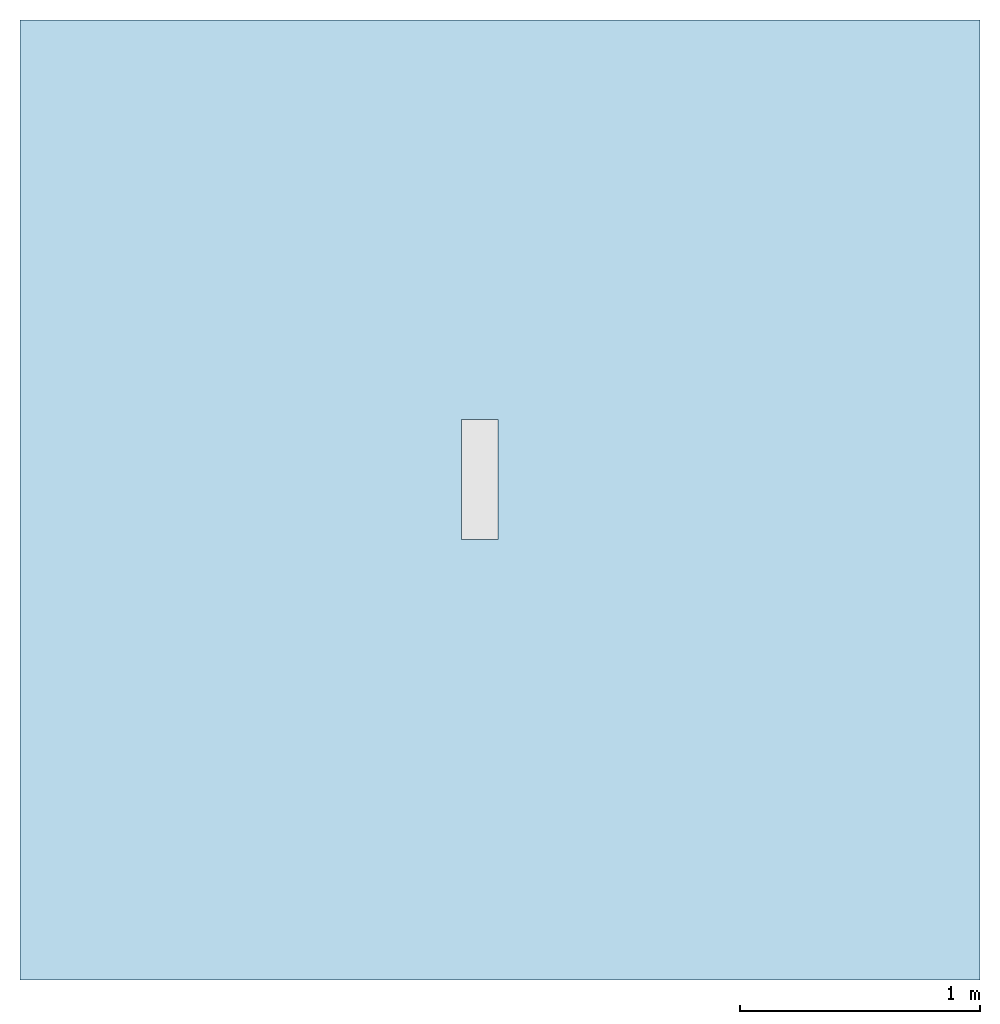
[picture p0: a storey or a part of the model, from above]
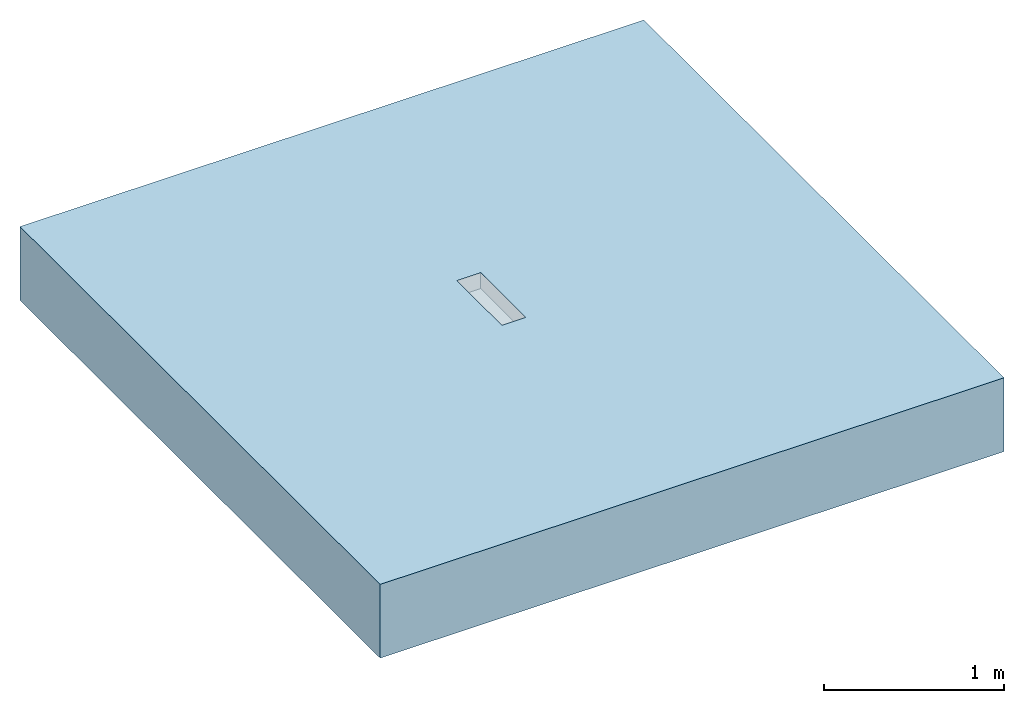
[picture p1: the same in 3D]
Properties of the parts of a building model (IFC2X3)

# File
Description: ViewDefinition [CoordinationView]
File name: 105178 - End Outlet Channel - 500mm LG - Invert Depth 95mm.ifc
Time: 2014-03-19T14:24:23
Written by: Autodesk Revit 2013
Made in: 20120221_2030(x64)

# IfcProject, Project Number
LongName: Project Name; Phase: Project Status

# IfcSite, Default
RefLatitude: 42, 21, 30, 344238; RefLongitude: -71, -3, -35, -194702; RefElevation: 0 mm

# IfcBuilding
Pset_BuildingCommon - NumberOfStoreys: 1
Other - Client Name: Owner; Project Name: Project Name; Project Number: Project Number; Project Address: ## Street City, State Zip; Project Issue Date: Issue Date; Project Status: Project Status

# IfcBuildingStorey, Level 1
LongName: Level 1; Elevation: 0 mm
Constraints - Elevation Base: 0; Elevation: 0 mm
Graphics - Line Weight: 1; Line Pattern: Center; Symbol at End 1 Default: no; Symbol at End 2 Default: yes; Color: 0; Symbol: M_Level Head - Circle: M_Level Head - Circle
Dimensions - Computation Height: 0 mm
Identity Data - Name: Level 1; Building Story: yes; Structural: no

# IfcFlowTerminal: 105178 - End Outlet Channel - 500mm LG - Invert Depth 95mm, ACO BD Modular 125 Inline Outlet Units:105178 - End Outlet Channel - 500mm LG - Invert Depth 95mm:105178 - End Outlet Channel - 500mm LG - Invert Depth 95mm:227583
In: Level 1
Material: Stainless Steel AISI 304, Polystyrene, High Impact
Identity Data - Watermarked With: BIM Manager Premium Suite.; Fax: +44 (0)1462 851490; Telephone: +44 (0)1462 816666; Watermark1: This file is the property of ACO Technologies PLC.; Website: www.acobd.com; E-mail Technical: abdtechnical@aco.co.uk; E-mail Sales: abdcommercial@aco.co.uk; Watermarked By: www.acobd.com; Address: ACO Business Centre, Caxton Road, Bedford, MK41 0LF; Manufacturer: ACO Building Drainage; Watermark2: This file is water marked and users are prohibited to reproduce, adapt, distribute this information.; Cost: 0; Mark: 5
Construction - 105519 - Slotted Locked - Stainless Steel 304 - 500mm long: no; 105537 - Intercept Locked - Stainless Steel 304 - 500mm long: no; 105529 - Quadrato - Stainless Steel 304 - 1000mm long: no; 105518 - Slotted Locked - Stainless Steel 304 - 1000mm long: no; 96818 - Grating - Heal Safe - Stainless Steel 304 - 1000mm long: no; 105845 - Slip Resistant Intercept - Stainless Steel 304 - 1000mm long: no; 105520 - Slotted Locked - Stainless Steel 304 - 1000mm long: no; 96819 - Grating - Heal Safe - Stainless Steel 304 - 500mm long: no; 105846 - Slip Resistant Intercept - Stainless Steel 304 - 500mm long: no; 21720 - Grating - Plain Mesh - Stainless Steel 304 - 500mm long: no; 105539 - Intercept - Stainless Steel 304 - 500mm long: no; 402072 - Grating - Heal Safe Locked - Stainless Steel 304 - 500mm long: no; 105536 - Intercept Locked - Stainless Steel 304 - 1000mm long: no; 105528 - Quadrato Locked - Stainless Steel 304 - 500mm long: no; 21810 - Grating - Slip Resistant Mesh - Stainless Steel 304 - 1000mm long: no; 21510 - Sediment Basket: no; 26270_PVC Infill: yes; 105521 - Slotted Locked - Stainless Steel 304 - 500mm long: no; 97235 - Sieve: no; 21820 - Grating - Plain Mesh - Stainless Steel 304 - 1000mm long: no; 21710 - Grating - Slip Resistant Mesh - Stainless Steel 304 - 500mm long: no; 21741 - Ladder - Stainless Steel 304 - 1000mm long: no; End Plate Invert 2: no; 21690 - Plastic - White Plastic - 1000mm long: no; 105505 - Perforated Locked - Stainless Steel 304 - 500mm long: no; 105538 - Intercept - Stainless Steel 304 - 1000mm long: no; 21610 - Grating - Slip Resistant Mesh - Stainless Steel 304 - 1000mm long: no; 105527 - Quadrato Locked - Stainless Steel 304 - 1000mm long: no; 21910 - Grating - Slip Resistant Mesh - Stainless Steel 304 - 500mm long: no; 21790 - Plastic - White Plastic - 500mm long: no; 105848 - Slip Resistant Intercept Locked - Stainless Steel 304 - 500mm long: no; 105847 - Slip Resistant Intercept Locked - Stainless Steel 304 - 1000mm long: no; 21740 - Ladder - Stainless Steel 304 - 500mm long: no; End Plate Invert 1: no; 49061 & 49062_Vinyl Seal: no; 21920 - Grating - Plain Mesh - Stainless Steel 304 - 500mm long: no; 402071 - Grating - Heal Safe Locked - Stainless Steel 304 - 1000mm long: no; 105530 - Quadrato - Stainless Steel 304 - 500mm long: no; 105841 - Slip Resistant Quadrato - Stainless Steel 304 - 1000mm long: no; 97217 - Outlet Foul Air Trap: no; 21620 - Grating - Plain Mesh - Stainless Steel 304 - 1000mm long: no; 105504 - Perforated Locked - Stainless Steel 304 - 1000mm long: no; 10735 - Composite - White Composite - 500mm long: no; 105843 - Slip Resistant Quadrato Locked - Stainless Steel 304 - 1000mm long: no; 105842 - Slip Resistant Quadrato - Stainless Steel 304 - 500mm long: no; 15704 - Composite - Black Composite - 500mm long: no; 105844 - Slip Resistant Quadrato Locked - Stainless Steel 304 - 500mm long: no; Detail 50mm: no; Detail 110mm: no; Detail 125mm: no; Detail 95mm: yes; Detail 80mm: no; Grating: yes; Detail 65mm: no
Other - Rigid PVC Extrusion (49061): 0 mm; Neoprene Gasket: 1; PVC Infill (26270): 1000 mm; Flexible PVC Seal (49062): 0 mm; Centre Spigot Outlets 1000mm Channel: no; End Spigot Outlets 500mm Channels: yes; Invert Depth Detail: 96.5 mm; Centre Spigot Outlets 500mm Channel: no; Number: 10; End Spigot Outlets 1000mm Channels: no; Spigot Outlets Channels: yes
Phasing - Phase Created: New Construction
Mechanical - System Classification: Sanitary
Constraints - Level: Level: Level 1
Model Properties - Product Code 97235: Sieve - Stainless Steel 304 - 0.1kg; Grating Product Code 105844: Load Class A15 - Slip Resistant Quadrato Locked - Stainless Steel 304 - 500mm long - 1.6kg; Grating Product Code 21920: Load Class C250 - Plain Mesh - Stainless Steel 304 - 500mm long - 2.2kg; Grating Product Code 10735: Load Class C250 - Composite - White Composite - 500mm long - 1.2kg; Grating Product Code 105518: Load Class A15 - Slotted Locked - Stainless Steel 304 - 1000mm long - 2.0kg; End Plate Product Code 105103: End Plate Stainless Steel 304 for Invert Depth - 95mm - 0.24Kg; Grating Product Code 105846: Load Class A15 - Slip Resistant Intercept - Stainless Steel 304 - 500mm long - 1.8kg; End Plate Product Code 105105: N/A; Product Code 97217: 110mm Ø Outlet Foul Air Trap - Stainless Steel 304 - Flow Rate 1.2l/s - 0.3kg; Grating Product Code 21741: Load Class C250 - Ladder - Stainless Steel 304 - 1000mm long - 3.4kg; Grating Product Code 105843: Load Class A15 - Slip Resistant Quadrato Locked - Stainless Steel 304 - 1000mm long - 3.2kg; Product Code 21510: Sediment Basket - Stainless Steel 304 - 0.1kg; Grating Product Code 105536: Load Class A15 - Intercept Locked - Stainless Steel 304 - 1000mm long - 3.6kg; Grating Product Code 21740: Load Class C250 - Ladder - Stainless Steel 304 - 500mm long - 2.0kg; Grating Product Code 105504: Load Class C250 - Perforated Locked - Stainless Steel 304 - 1000mm long - 3.6kg; Grating Product Code 21810: Load Class C250 - Slip Resistant Mesh - Stainless Steel 304 - 1000mm long - 4.2kg; Grating Product Code 105527: Load Class A15 - Quadrato Locked - Stainless Steel 304 - 1000mm long - 3.2kg; Grating Product Code 15704: Load Class C250 - Composite - Black Composite - 500mm long - 1.2kg; Grating Product Code 105537: Load Class A15 - Intercept Locked - Stainless Steel 304 - 500mm long - 1.8kg; Grating Product Code 21820: Load Class C250 - Plain Mesh - Stainless Steel 304 - 1000mm long - 4.2kg; Grating Product Code 105520: Load Class C250 - Slotted Locked - Stainless Steel 304 - 1000mm long - 4.7kg; Grating Product Code 105530: Load Class A15 - Quadrato - Stainless Steel 304 - 500mm long - 1.6kg; Grating Product Code 21710: Load Class A15 - Slip Resistant Mesh - Stainless Steel 304 - 500mm long - 1.6kg; Grating Product Code 105519: Load Class A15 - Slotted Locked - Stainless Steel 304 - 500mm long - 1.0kg; Grating Product Code 105528: Load Class A15 - Quadrato Locked - Stainless Steel 304 - 500mm long - 1.6kg; Grating Product Code 96819: Load Class B125 - Heal Safe - Stainless Steel 304 - 500mm long - 2.0kg; Grating Product Code 96818: Load Class B125 - Heal Safe - Stainless Steel 304 - 1000mm long - 3.4kg; Grating Product Code 105538: Load Class A15 - Intercept - Stainless Steel 304 - 1000mm long - 3.6kg; Grating Product Code 21910: Load Class C250 - Slip Resistant Mesh - Stainless Steel 304 - 500mm long - 2.2kg; Grating Product Code 402072: Load Class B125 - Heal Safe Locked - Stainless Steel 304 - 500mm long - 2.0kg; Grating Product Code 105848: Load Class A15 - Slip Resistant Intercept Locked - Stainless Steel 304 - 500mm long - 1.8kg; Grating Product Code 402071: Load Class B125 - Heal Safe Locked - Stainless Steel 304 - 1000mm long - 3.4kg; Grating Product Code 105505: Load Class C250 - Perforated Locked - Stainless Steel 304 - 500mm long - 1.8kg; Grating Product Code 21610: Load Class A15 - Slip Resistant Mesh - Stainless Steel 304 - 1000mm long - 3.0kg; Grating Product Code 21720: Load Class A15 - Plain Mesh - Stainless Steel 304 - 500mm long - 1.6kg; Grating Product Code 105539: Load Class A15 - Intercept - Stainless Steel 304 - 500mm long - 1.8kg; Grating Product Code 21620: Load Class A15 - Plain Mesh - Stainless Steel 304 - 1000mm long - 3.0kg; End Plate Product Code 105102: N/A; Grating Product Code 105845: Load Class A15 - Slip Resistant Intercept - Stainless Steel 304 - 1000mm long - 3.6kg; End Plate Product Code 105104: N/A; Grating Product Code 105847: Load Class A15 - Slip Resistant Intercept Locked - Stainless Steel 304 - 1000mm long - 3.6kg; Grating Product Code 21790: Load Class A15 - Plastic - White Plastic - 500mm long - 0.6kg; End Plate Product Code 105101: N/A; End Plate Product Code 105100: N/A; Grating Product Code 105521: Load Class C250 - Slotted Locked - Stainless Steel 304 - 500mm long - 2.3kg; Grating Product Code 105529: Load Class A15 - Quadrato - Stainless Steel 304 - 1000mm long - 3.2kg; Grating Product Code 105841: Load Class A15 - Slip Resistant Quadrato - Stainless Steel 304 - 1000mm long - 3.2kg; Grating Product Code 21690: Load Class A15 - Plastic - White Plastic - 1000mm long - 1.2kg; Grating Product Code 105842: Load Class A15 - Slip Resistant Quadrato - Stainless Steel 304 - 500mm long - 1.6kg
Dimensions - Grating Void Cut Length: 500 mm; End Connection Plate End: -500 mm; End Connection Plate Start: -497 mm; Grating Height: 21 mm; Depth: 74 mm; Invert Depth: 95 mm; Spigot Distance: 75 mm; Endplate Position: 500 mm; Floor Cut Void Height: 107.8 mm; Length Channel: -497 mm
General - Product Standard: BS EN 1433:2002 CE marked; Seal Material: Neoprene; Installation guidelines: X:\Electronic Literature\ABD Electronic Literature\Standard Stainless Steel and Galvanised Steel Channels\ACO Modular 125\ACO Modular 125.pdf; Seal Recyclable: Fully recyclable; Product Description: ACO Modular 125 500mm End Outlet Unit; Dimensions (LxWxH): 500 x 153 x 95; Channel Colour: Mid Grey; Weight (Kg): 3.3; Seal Recycled Material Content: 0%; Price: POA - contact ACO; Product Range: ACO Modular 125; Channel Material: Stainless Steel Grade 304; Load Class: A15 - C250; Product Code: 105178; Seal Colour: Black; Product Type: Stainless Steel Channel Drainage System; NBS Specification: NBS Section Q10 Kerbs/edgings/channels/paving accessories, Clause 180 Drainage Channel Systems; Channel Recyclable: Fully recyclable; Channel Recycled Material Content: 60-70%; Maintenance guidelines: X:\Electronic Literature\ABD Electronic Literature\Standard Stainless Steel and Galvanised Steel Channels\ACO Modular 125\ACO Modular 125.pdf

# IfcOpeningElement: Recess
In: Level 1
Dimensions - Volume: 7990764258 mm3; Perimeter: 16000 mm; Area: 16000000 mm2; Thickness: 500 mm
Constraints - Level: Level: Level 1; Related to Mass: no; Height Offset From Level: 0 mm; Room Bounding: yes
Phasing - Phase Created: New Construction
Structural - Structural: no; Enable Analytical Model: no
Analytical Properties - Absorptance: 0.1; Thermal Resistance (R): 0.478011; Roughness: 1; Thermal mass: 755550; Heat Transfer Coefficient (U): 2.092
Construction - Function: 0; Default Thickness: 500 mm
Graphics - Coarse Scale Fill Color: 0
Materials and Finishes - Structural Material: Concrete, Broom Finish

# IfcSlab: Floor:Generic Floor - 500mm, Floor:Generic Floor - 500mm:193825
In: Level 1
PredefinedType: FLOOR; Material: Concrete, Broom Finish 500 mm
Dimensions - Volume: 7990764258 mm3; Perimeter: 16000 mm; Area: 16000000 mm2; Thickness: 500 mm
Constraints - Level: Level: Level 1; Related to Mass: no; Height Offset From Level: 0 mm; Room Bounding: yes
Phasing - Phase Created: New Construction
Structural - Structural: no; Enable Analytical Model: no
Pset_SlabCommon - Reference: Generic Floor - 500mm; IsExternal: no; LoadBearing: yes
Analytical Properties - Absorptance: 0.1; Thermal Resistance (R): 0.478011; Roughness: 1; Thermal mass: 755550; Heat Transfer Coefficient (U): 2.092
Construction - Function: 0; Default Thickness: 500 mm
Graphics - Coarse Scale Fill Color: 0
Materials and Finishes - Structural Material: Concrete, Broom Finish
